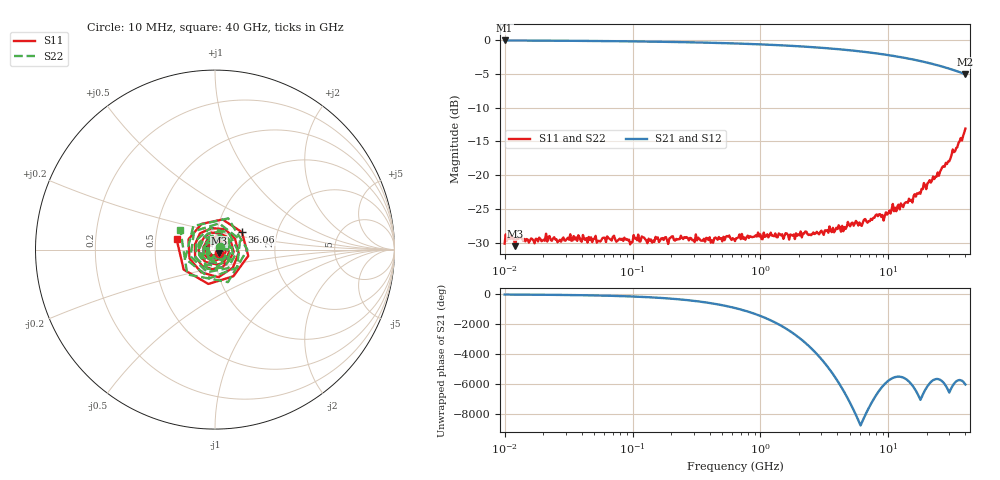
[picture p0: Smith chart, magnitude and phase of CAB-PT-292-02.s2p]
! CAL-ELEKTRA — DATOS SINTÉTICOS DE EJEMPLO: no son una medida real.
! Cable simulado CAB-PT-292-02: 1.0 m, 10 MHz – 40 GHz
# HZ S RI R 50
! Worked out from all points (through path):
!   401 points, 10 MHz to 40 GHz, reference 50 ohm
!   highest |S21| = -0.06 dB at 10 MHz (marker M1); lowest = -5.1 dB at 40 GHz (marker M2)
!   lowest |S11| = -30.5 dB at 12.05 MHz (marker M3), VSWR 1.06, Z = 52.3 - j2.04 ohm
!   |S11| at or under -10 dB: start of sweep to end of sweep
!   |S22| runs from -30.5 to -13.1 dB; largest |S21 - S12| = 0
!   S11 on the Smith chart (normalised r, x): 10 MHz: 1.05, -0.04; 36.06 GHz: 1.32, +0.27; 40 GHz: 0.64, +0.08
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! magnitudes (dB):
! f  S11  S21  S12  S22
! 10 MHz  -30.1  -0.1  -0.1  -30.1
! 10.64 MHz  -29.3  -0.1  -0.1  -29.3
! 12.05 MHz  -30.5  -0.1  -0.1  -30.5
! 40.12 MHz  -29.8  -0.1  -0.1  -29.8
! 54.75 MHz  -29.7  -0.1  -0.1  -29.7
! 60.74 MHz  -29.2  -0.2  -0.2  -29.2
! 90.06 MHz  -29.4  -0.2  -0.2  -29.4
! 95.84 MHz  -30.2  -0.2  -0.2  -30.2
! 106.3 MHz  -29.3  -0.2  -0.2  -29.3
! 136.3 MHz  -29.7  -0.2  -0.2  -29.7
! 160.9 MHz  -29.9  -0.2  -0.2  -29.9
! 645.7 MHz  -29.3  -0.5  -0.5  -29.3
! 2.537 GHz  -28.7  -1.0  -1.0  -28.7
! 4.441 GHz  -28.3  -1.4  -1.4  -28.3
! 5.03 GHz  -27.5  -1.5  -1.5  -27.5
! 6.062 GHz  -27.4  -1.7  -1.7  -27.4
! 10.18 GHz  -25.2  -2.3  -2.3  -25.2
! 14.78 GHz  -23.8  -2.8  -2.8  -23.8
! 23.82 GHz  -20.2  -3.7  -3.7  -20.2
! 29.92 GHz  -17.9  -4.2  -4.2  -17.9
! 36.06 GHz  -15.0  -4.7  -4.7  -15.0
! 40 GHz  -13.1  -5.1  -5.1  -13.1
